VERSION 5.7 ;
  NOWIREEXTENSIONATPIN ON ;
  DIVIDERCHAR "/" ;
  BUSBITCHARS "[]" ;
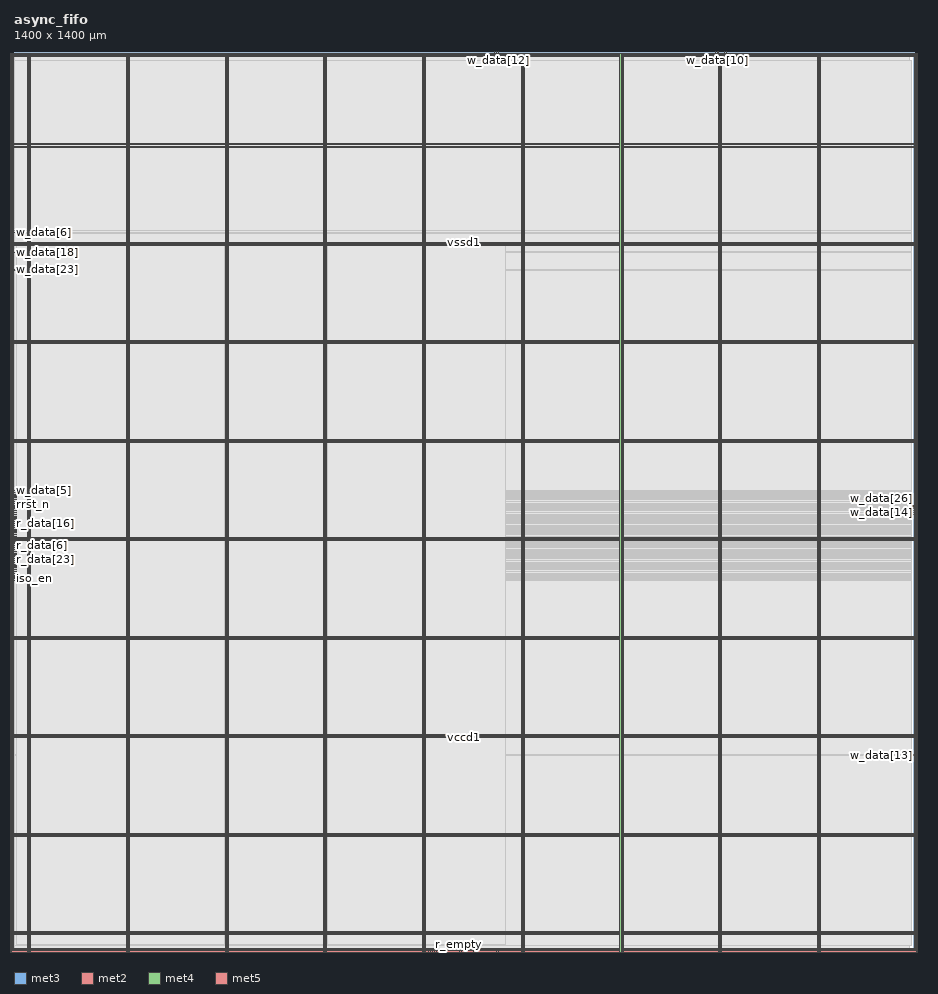
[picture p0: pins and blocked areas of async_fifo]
MACRO async_fifo
  CLASS BLOCK ;
  FOREIGN async_fifo ;
  ORIGIN 0.000 0.000 ;
  SIZE 1400.000 BY 1400.000 ;
  PIN iso_en
    DIRECTION INPUT ;
    USE SIGNAL ;
    ANTENNAGATEAREA 0.159000 ;
    PORT
      LAYER met3 ;
        RECT 0.000 581.440 4.000 582.040 ;
    END
  END iso_en
  PIN r_data[0]
    DIRECTION OUTPUT ;
    USE SIGNAL ;
    ANTENNADIFFAREA 3.180800 ;
    PORT
      LAYER met3 ;
        RECT 0.000 697.040 4.000 697.640 ;
    END
  END r_data[0]
  PIN r_data[10]
    DIRECTION OUTPUT ;
    USE SIGNAL ;
    ANTENNADIFFAREA 3.180800 ;
    PORT
      LAYER met3 ;
        RECT 0.000 693.640 4.000 694.240 ;
    END
  END r_data[10]
  PIN r_data[11]
    DIRECTION OUTPUT ;
    USE SIGNAL ;
    ANTENNADIFFAREA 3.180800 ;
    PORT
      LAYER met3 ;
        RECT 0.000 676.640 4.000 677.240 ;
    END
  END r_data[11]
  PIN r_data[12]
    DIRECTION OUTPUT ;
    USE SIGNAL ;
    ANTENNADIFFAREA 3.180800 ;
    PORT
      LAYER met3 ;
        RECT 0.000 584.840 4.000 585.440 ;
    END
  END r_data[12]
  PIN r_data[13]
    DIRECTION OUTPUT ;
    USE SIGNAL ;
    ANTENNADIFFAREA 3.180800 ;
    PORT
      LAYER met3 ;
        RECT 0.000 595.040 4.000 595.640 ;
    END
  END r_data[13]
  PIN r_data[14]
    DIRECTION OUTPUT ;
    USE SIGNAL ;
    ANTENNADIFFAREA 3.180800 ;
    PORT
      LAYER met3 ;
        RECT 0.000 629.040 4.000 629.640 ;
    END
  END r_data[14]
  PIN r_data[15]
    DIRECTION OUTPUT ;
    USE SIGNAL ;
    ANTENNADIFFAREA 3.180800 ;
    PORT
      LAYER met3 ;
        RECT 0.000 673.240 4.000 673.840 ;
    END
  END r_data[15]
  PIN r_data[16]
    DIRECTION OUTPUT ;
    USE SIGNAL ;
    ANTENNADIFFAREA 3.180800 ;
    PORT
      LAYER met3 ;
        RECT 0.000 666.440 4.000 667.040 ;
    END
  END r_data[16]
  PIN r_data[17]
    DIRECTION OUTPUT ;
    USE SIGNAL ;
    ANTENNADIFFAREA 3.180800 ;
    PORT
      LAYER met3 ;
        RECT 0.000 635.840 4.000 636.440 ;
    END
  END r_data[17]
  PIN r_data[18]
    DIRECTION OUTPUT ;
    USE SIGNAL ;
    ANTENNADIFFAREA 3.180800 ;
    PORT
      LAYER met3 ;
        RECT 0.000 680.040 4.000 680.640 ;
    END
  END r_data[18]
  PIN r_data[19]
    DIRECTION OUTPUT ;
    USE SIGNAL ;
    ANTENNADIFFAREA 3.180800 ;
    PORT
      LAYER met3 ;
        RECT 0.000 669.840 4.000 670.440 ;
    END
  END r_data[19]
  PIN r_data[1]
    DIRECTION OUTPUT ;
    USE SIGNAL ;
    ANTENNADIFFAREA 3.180800 ;
    PORT
      LAYER met3 ;
        RECT 0.000 618.840 4.000 619.440 ;
    END
  END r_data[1]
  PIN r_data[20]
    DIRECTION OUTPUT ;
    USE SIGNAL ;
    ANTENNADIFFAREA 3.180800 ;
    PORT
      LAYER met3 ;
        RECT 0.000 642.640 4.000 643.240 ;
    END
  END r_data[20]
  PIN r_data[21]
    DIRECTION OUTPUT ;
    USE SIGNAL ;
    ANTENNADIFFAREA 3.180800 ;
    PORT
      LAYER met3 ;
        RECT 0.000 612.040 4.000 612.640 ;
    END
  END r_data[21]
  PIN r_data[22]
    DIRECTION OUTPUT ;
    USE SIGNAL ;
    ANTENNADIFFAREA 3.180800 ;
    PORT
      LAYER met3 ;
        RECT 0.000 622.240 4.000 622.840 ;
    END
  END r_data[22]
  PIN r_data[23]
    DIRECTION OUTPUT ;
    USE SIGNAL ;
    ANTENNADIFFAREA 3.180800 ;
    PORT
      LAYER met3 ;
        RECT 0.000 598.440 4.000 599.040 ;
    END
  END r_data[23]
  PIN r_data[24]
    DIRECTION OUTPUT ;
    USE SIGNAL ;
    ANTENNADIFFAREA 3.180800 ;
    PORT
      LAYER met3 ;
        RECT 0.000 659.640 4.000 660.240 ;
    END
  END r_data[24]
  PIN r_data[25]
    DIRECTION OUTPUT ;
    USE SIGNAL ;
    ANTENNADIFFAREA 3.180800 ;
    PORT
      LAYER met3 ;
        RECT 0.000 608.640 4.000 609.240 ;
    END
  END r_data[25]
  PIN r_data[26]
    DIRECTION OUTPUT ;
    USE SIGNAL ;
    ANTENNADIFFAREA 3.180800 ;
    PORT
      LAYER met3 ;
        RECT 0.000 601.840 4.000 602.440 ;
    END
  END r_data[26]
  PIN r_data[27]
    DIRECTION OUTPUT ;
    USE SIGNAL ;
    ANTENNADIFFAREA 3.180800 ;
    PORT
      LAYER met3 ;
        RECT 0.000 663.040 4.000 663.640 ;
    END
  END r_data[27]
  PIN r_data[28]
    DIRECTION OUTPUT ;
    USE SIGNAL ;
    ANTENNADIFFAREA 3.180800 ;
    PORT
      LAYER met3 ;
        RECT 0.000 591.640 4.000 592.240 ;
    END
  END r_data[28]
  PIN r_data[29]
    DIRECTION OUTPUT ;
    USE SIGNAL ;
    ANTENNADIFFAREA 3.180800 ;
    PORT
      LAYER met3 ;
        RECT 0.000 690.240 4.000 690.840 ;
    END
  END r_data[29]
  PIN r_data[2]
    DIRECTION OUTPUT ;
    USE SIGNAL ;
    ANTENNADIFFAREA 3.180800 ;
    PORT
      LAYER met3 ;
        RECT 0.000 588.240 4.000 588.840 ;
    END
  END r_data[2]
  PIN r_data[30]
    DIRECTION OUTPUT ;
    USE SIGNAL ;
    ANTENNADIFFAREA 3.180800 ;
    PORT
      LAYER met3 ;
        RECT 0.000 605.240 4.000 605.840 ;
    END
  END r_data[30]
  PIN r_data[31]
    DIRECTION OUTPUT ;
    USE SIGNAL ;
    ANTENNADIFFAREA 3.180800 ;
    PORT
      LAYER met3 ;
        RECT 0.000 615.440 4.000 616.040 ;
    END
  END r_data[31]
  PIN r_data[3]
    DIRECTION OUTPUT ;
    USE SIGNAL ;
    ANTENNADIFFAREA 3.180800 ;
    PORT
      LAYER met3 ;
        RECT 0.000 646.040 4.000 646.640 ;
    END
  END r_data[3]
  PIN r_data[4]
    DIRECTION OUTPUT ;
    USE SIGNAL ;
    ANTENNADIFFAREA 3.180800 ;
    PORT
      LAYER met3 ;
        RECT 0.000 625.640 4.000 626.240 ;
    END
  END r_data[4]
  PIN r_data[5]
    DIRECTION OUTPUT ;
    USE SIGNAL ;
    ANTENNADIFFAREA 3.180800 ;
    PORT
      LAYER met3 ;
        RECT 0.000 656.240 4.000 656.840 ;
    END
  END r_data[5]
  PIN r_data[6]
    DIRECTION OUTPUT ;
    USE SIGNAL ;
    ANTENNADIFFAREA 3.180800 ;
    PORT
      LAYER met3 ;
        RECT 0.000 632.440 4.000 633.040 ;
    END
  END r_data[6]
  PIN r_data[7]
    DIRECTION OUTPUT ;
    USE SIGNAL ;
    ANTENNADIFFAREA 3.180800 ;
    PORT
      LAYER met3 ;
        RECT 0.000 649.440 4.000 650.040 ;
    END
  END r_data[7]
  PIN r_data[8]
    DIRECTION OUTPUT ;
    USE SIGNAL ;
    ANTENNADIFFAREA 3.180800 ;
    PORT
      LAYER met3 ;
        RECT 0.000 652.840 4.000 653.440 ;
    END
  END r_data[8]
  PIN r_data[9]
    DIRECTION OUTPUT ;
    USE SIGNAL ;
    ANTENNADIFFAREA 3.180800 ;
    PORT
      LAYER met3 ;
        RECT 0.000 639.240 4.000 639.840 ;
    END
  END r_data[9]
  PIN r_empty
    DIRECTION OUTPUT ;
    USE SIGNAL ;
    ANTENNADIFFAREA 3.180800 ;
    PORT
      LAYER met2 ;
        RECT 692.390 0.000 692.670 4.000 ;
    END
  END r_empty
  PIN r_inc
    DIRECTION INPUT ;
    USE SIGNAL ;
    ANTENNAGATEAREA 0.426000 ;
    PORT
      LAYER met2 ;
        RECT 695.610 0.000 695.890 4.000 ;
    END
  END r_inc
  PIN rclk
    DIRECTION INPUT ;
    USE SIGNAL ;
    ANTENNAGATEAREA 0.852000 ;
    PORT
      LAYER met3 ;
        RECT 0.000 686.840 4.000 687.440 ;
    END
  END rclk
  PIN rrst_n
    DIRECTION INPUT ;
    USE SIGNAL ;
    ANTENNAGATEAREA 0.990000 ;
    PORT
      LAYER met3 ;
        RECT 0.000 683.440 4.000 684.040 ;
    END
  END rrst_n
  PIN vccd1
    DIRECTION INOUT ;
    USE POWER ;
    PORT
      LAYER met4 ;
        RECT -2.080 3.280 -0.480 1394.800 ;
    END
    PORT
      LAYER met5 ;
        RECT -2.080 3.280 1401.860 4.880 ;
    END
    PORT
      LAYER met5 ;
        RECT -2.080 1393.200 1401.860 1394.800 ;
    END
    PORT
      LAYER met4 ;
        RECT 1400.260 3.280 1401.860 1394.800 ;
    END
    PORT
      LAYER met4 ;
        RECT 21.040 -0.020 22.640 1398.100 ;
    END
    PORT
      LAYER met4 ;
        RECT 174.640 -0.020 176.240 1398.100 ;
    END
    PORT
      LAYER met4 ;
        RECT 328.240 -0.020 329.840 1398.100 ;
    END
    PORT
      LAYER met4 ;
        RECT 481.840 -0.020 483.440 1398.100 ;
    END
    PORT
      LAYER met4 ;
        RECT 635.440 -0.020 637.040 1398.100 ;
    END
    PORT
      LAYER met4 ;
        RECT 789.040 -0.020 790.640 1398.100 ;
    END
    PORT
      LAYER met4 ;
        RECT 942.640 -0.020 944.240 1398.100 ;
    END
    PORT
      LAYER met4 ;
        RECT 1096.240 -0.020 1097.840 1398.100 ;
    END
    PORT
      LAYER met4 ;
        RECT 1249.840 -0.020 1251.440 1398.100 ;
    END
    PORT
      LAYER met5 ;
        RECT -5.380 26.730 1405.160 28.330 ;
    END
    PORT
      LAYER met5 ;
        RECT -5.380 179.910 1405.160 181.510 ;
    END
    PORT
      LAYER met5 ;
        RECT -5.380 333.090 1405.160 334.690 ;
    END
    PORT
      LAYER met5 ;
        RECT -5.380 486.270 1405.160 487.870 ;
    END
    PORT
      LAYER met5 ;
        RECT -5.380 639.450 1405.160 641.050 ;
    END
    PORT
      LAYER met5 ;
        RECT -5.380 792.630 1405.160 794.230 ;
    END
    PORT
      LAYER met5 ;
        RECT -5.380 945.810 1405.160 947.410 ;
    END
    PORT
      LAYER met5 ;
        RECT -5.380 1098.990 1405.160 1100.590 ;
    END
    PORT
      LAYER met5 ;
        RECT -5.380 1252.170 1405.160 1253.770 ;
    END
  END vccd1
  PIN vssd1
    DIRECTION INOUT ;
    USE GROUND ;
    PORT
      LAYER met4 ;
        RECT -5.380 -0.020 -3.780 1398.100 ;
    END
    PORT
      LAYER met5 ;
        RECT -5.380 -0.020 1405.160 1.580 ;
    END
    PORT
      LAYER met5 ;
        RECT -5.380 1396.500 1405.160 1398.100 ;
    END
    PORT
      LAYER met4 ;
        RECT 1403.560 -0.020 1405.160 1398.100 ;
    END
    PORT
      LAYER met4 ;
        RECT 24.340 -0.020 25.940 1398.100 ;
    END
    PORT
      LAYER met4 ;
        RECT 177.940 -0.020 179.540 1398.100 ;
    END
    PORT
      LAYER met4 ;
        RECT 331.540 -0.020 333.140 1398.100 ;
    END
    PORT
      LAYER met4 ;
        RECT 485.140 -0.020 486.740 1398.100 ;
    END
    PORT
      LAYER met4 ;
        RECT 638.740 -0.020 640.340 1398.100 ;
    END
    PORT
      LAYER met4 ;
        RECT 792.340 -0.020 793.940 1398.100 ;
    END
    PORT
      LAYER met4 ;
        RECT 945.940 -0.020 947.540 1398.100 ;
    END
    PORT
      LAYER met4 ;
        RECT 1099.540 -0.020 1101.140 1398.100 ;
    END
    PORT
      LAYER met4 ;
        RECT 1253.140 -0.020 1254.740 1398.100 ;
    END
    PORT
      LAYER met5 ;
        RECT -5.380 30.030 1405.160 31.630 ;
    END
    PORT
      LAYER met5 ;
        RECT -5.380 183.210 1405.160 184.810 ;
    END
    PORT
      LAYER met5 ;
        RECT -5.380 336.390 1405.160 337.990 ;
    END
    PORT
      LAYER met5 ;
        RECT -5.380 489.570 1405.160 491.170 ;
    END
    PORT
      LAYER met5 ;
        RECT -5.380 642.750 1405.160 644.350 ;
    END
    PORT
      LAYER met5 ;
        RECT -5.380 795.930 1405.160 797.530 ;
    END
    PORT
      LAYER met5 ;
        RECT -5.380 949.110 1405.160 950.710 ;
    END
    PORT
      LAYER met5 ;
        RECT -5.380 1102.290 1405.160 1103.890 ;
    END
    PORT
      LAYER met5 ;
        RECT -5.380 1255.470 1405.160 1257.070 ;
    END
  END vssd1
  PIN w_data[0]
    DIRECTION INPUT ;
    USE SIGNAL ;
    ANTENNAGATEAREA 0.495000 ;
    PORT
      LAYER met3 ;
        RECT 1396.000 680.040 1400.000 680.640 ;
    END
  END w_data[0]
  PIN w_data[10]
    DIRECTION INPUT ;
    USE SIGNAL ;
    ANTENNAGATEAREA 0.852000 ;
    PORT
      LAYER met2 ;
        RECT 1094.890 1396.000 1095.170 1400.000 ;
    END
  END w_data[10]
  PIN w_data[11]
    DIRECTION INPUT ;
    USE SIGNAL ;
    ANTENNAGATEAREA 0.852000 ;
    PORT
      LAYER met2 ;
        RECT 644.090 0.000 644.370 4.000 ;
    END
  END w_data[11]
  PIN w_data[12]
    DIRECTION INPUT ;
    USE SIGNAL ;
    ANTENNAGATEAREA 0.852000 ;
    PORT
      LAYER met2 ;
        RECT 753.570 1396.000 753.850 1400.000 ;
    END
  END w_data[12]
  PIN w_data[13]
    DIRECTION INPUT ;
    USE SIGNAL ;
    ANTENNAGATEAREA 0.495000 ;
    PORT
      LAYER met3 ;
        RECT 1396.000 306.040 1400.000 306.640 ;
    END
  END w_data[13]
  PIN w_data[14]
    DIRECTION INPUT ;
    USE SIGNAL ;
    ANTENNAGATEAREA 0.852000 ;
    PORT
      LAYER met3 ;
        RECT 1396.000 683.440 1400.000 684.040 ;
    END
  END w_data[14]
  PIN w_data[15]
    DIRECTION INPUT ;
    USE SIGNAL ;
    ANTENNAGATEAREA 0.247500 ;
    PORT
      LAYER met2 ;
        RECT 750.350 1396.000 750.630 1400.000 ;
    END
  END w_data[15]
  PIN w_data[16]
    DIRECTION INPUT ;
    USE SIGNAL ;
    ANTENNAGATEAREA 0.852000 ;
    PORT
      LAYER met3 ;
        RECT 0.000 714.040 4.000 714.640 ;
    END
  END w_data[16]
  PIN w_data[17]
    DIRECTION INPUT ;
    USE SIGNAL ;
    ANTENNAGATEAREA 0.990000 ;
    PORT
      LAYER met2 ;
        RECT 1107.770 1396.000 1108.050 1400.000 ;
    END
  END w_data[17]
  PIN w_data[18]
    DIRECTION INPUT ;
    USE SIGNAL ;
    ANTENNAGATEAREA 0.852000 ;
    PORT
      LAYER met3 ;
        RECT 0.000 1088.040 4.000 1088.640 ;
    END
  END w_data[18]
  PIN w_data[19]
    DIRECTION INPUT ;
    USE SIGNAL ;
    ANTENNAGATEAREA 0.852000 ;
    PORT
      LAYER met2 ;
        RECT 647.310 0.000 647.590 4.000 ;
    END
  END w_data[19]
  PIN w_data[1]
    DIRECTION INPUT ;
    USE SIGNAL ;
    ANTENNAGATEAREA 0.852000 ;
    PORT
      LAYER met3 ;
        RECT 1396.000 686.840 1400.000 687.440 ;
    END
  END w_data[1]
  PIN w_data[20]
    DIRECTION INPUT ;
    USE SIGNAL ;
    ANTENNAGATEAREA 0.852000 ;
    PORT
      LAYER met2 ;
        RECT 650.530 0.000 650.810 4.000 ;
    END
  END w_data[20]
  PIN w_data[21]
    DIRECTION INPUT ;
    USE SIGNAL ;
    ANTENNAGATEAREA 0.990000 ;
    PORT
      LAYER met2 ;
        RECT 1091.670 1396.000 1091.950 1400.000 ;
    END
  END w_data[21]
  PIN w_data[22]
    DIRECTION INPUT ;
    USE SIGNAL ;
    ANTENNAGATEAREA 0.426000 ;
    PORT
      LAYER met3 ;
        RECT 1396.000 690.240 1400.000 690.840 ;
    END
  END w_data[22]
  PIN w_data[23]
    DIRECTION INPUT ;
    USE SIGNAL ;
    ANTENNAGATEAREA 0.852000 ;
    PORT
      LAYER met3 ;
        RECT 0.000 1060.840 4.000 1061.440 ;
    END
  END w_data[23]
  PIN w_data[24]
    DIRECTION INPUT ;
    USE SIGNAL ;
    ANTENNAGATEAREA 0.852000 ;
    PORT
      LAYER met2 ;
        RECT 653.750 0.000 654.030 4.000 ;
    END
  END w_data[24]
  PIN w_data[25]
    DIRECTION INPUT ;
    USE SIGNAL ;
    ANTENNAGATEAREA 0.990000 ;
    PORT
      LAYER met2 ;
        RECT 747.130 1396.000 747.410 1400.000 ;
    END
  END w_data[25]
  PIN w_data[26]
    DIRECTION INPUT ;
    USE SIGNAL ;
    ANTENNAGATEAREA 0.495000 ;
    PORT
      LAYER met3 ;
        RECT 1396.000 693.640 1400.000 694.240 ;
    END
  END w_data[26]
  PIN w_data[27]
    DIRECTION INPUT ;
    USE SIGNAL ;
    ANTENNAGATEAREA 0.852000 ;
    PORT
      LAYER met2 ;
        RECT 656.970 0.000 657.250 4.000 ;
    END
  END w_data[27]
  PIN w_data[28]
    DIRECTION INPUT ;
    USE SIGNAL ;
    ANTENNAGATEAREA 0.990000 ;
    PORT
      LAYER met3 ;
        RECT 0.000 710.640 4.000 711.240 ;
    END
  END w_data[28]
  PIN w_data[29]
    DIRECTION INPUT ;
    USE SIGNAL ;
    ANTENNAGATEAREA 0.852000 ;
    PORT
      LAYER met2 ;
        RECT 660.190 0.000 660.470 4.000 ;
    END
  END w_data[29]
  PIN w_data[2]
    DIRECTION INPUT ;
    USE SIGNAL ;
    ANTENNAGATEAREA 0.852000 ;
    PORT
      LAYER met3 ;
        RECT 0.000 707.240 4.000 707.840 ;
    END
  END w_data[2]
  PIN w_data[30]
    DIRECTION INPUT ;
    USE SIGNAL ;
    ANTENNAGATEAREA 0.990000 ;
    PORT
      LAYER met3 ;
        RECT 0.000 703.840 4.000 704.440 ;
    END
  END w_data[30]
  PIN w_data[31]
    DIRECTION INPUT ;
    USE SIGNAL ;
    ANTENNAGATEAREA 0.852000 ;
    PORT
      LAYER met2 ;
        RECT 663.410 0.000 663.690 4.000 ;
    END
  END w_data[31]
  PIN w_data[3]
    DIRECTION INPUT ;
    USE SIGNAL ;
    ANTENNAGATEAREA 0.852000 ;
    PORT
      LAYER met3 ;
        RECT 0.000 700.440 4.000 701.040 ;
    END
  END w_data[3]
  PIN w_data[4]
    DIRECTION INPUT ;
    USE SIGNAL ;
    ANTENNAGATEAREA 0.990000 ;
    PORT
      LAYER met3 ;
        RECT 0.000 578.040 4.000 578.640 ;
    END
  END w_data[4]
  PIN w_data[5]
    DIRECTION INPUT ;
    USE SIGNAL ;
    ANTENNAGATEAREA 0.990000 ;
    PORT
      LAYER met3 ;
        RECT 0.000 717.440 4.000 718.040 ;
    END
  END w_data[5]
  PIN w_data[6]
    DIRECTION INPUT ;
    USE SIGNAL ;
    ANTENNAGATEAREA 0.852000 ;
    PORT
      LAYER met3 ;
        RECT 0.000 1118.640 4.000 1119.240 ;
    END
  END w_data[6]
  PIN w_data[7]
    DIRECTION INPUT ;
    USE SIGNAL ;
    ANTENNAGATEAREA 0.852000 ;
    PORT
      LAYER met2 ;
        RECT 666.630 0.000 666.910 4.000 ;
    END
  END w_data[7]
  PIN w_data[8]
    DIRECTION INPUT ;
    USE SIGNAL ;
    ANTENNAGATEAREA 0.213000 ;
    PORT
      LAYER met2 ;
        RECT 1104.550 1396.000 1104.830 1400.000 ;
    END
  END w_data[8]
  PIN w_data[9]
    DIRECTION INPUT ;
    USE SIGNAL ;
    ANTENNAGATEAREA 0.990000 ;
    PORT
      LAYER met2 ;
        RECT 669.850 0.000 670.130 4.000 ;
    END
  END w_data[9]
  PIN w_full
    DIRECTION OUTPUT ;
    USE SIGNAL ;
    ANTENNADIFFAREA 3.180800 ;
    PORT
      LAYER met2 ;
        RECT 750.350 0.000 750.630 4.000 ;
    END
  END w_full
  PIN w_inc
    DIRECTION INPUT ;
    USE SIGNAL ;
    ANTENNAGATEAREA 0.426000 ;
    PORT
      LAYER met2 ;
        RECT 753.570 0.000 753.850 4.000 ;
    END
  END w_inc
  PIN wclk
    DIRECTION INPUT ;
    USE SIGNAL ;
    ANTENNAGATEAREA 1.286700 ;
    ANTENNADIFFAREA 0.434700 ;
    PORT
      LAYER met3 ;
        RECT 0.000 1122.040 4.000 1122.640 ;
    END
  END wclk
  PIN wrst_n
    DIRECTION INPUT ;
    USE SIGNAL ;
    ANTENNAGATEAREA 0.126000 ;
    PORT
      LAYER met2 ;
        RECT 714.930 0.000 715.210 4.000 ;
    END
  END wrst_n
  OBS
      LAYER nwell ;
        RECT 5.330 10.795 1394.450 1387.285 ;
      LAYER li1 ;
        RECT 5.520 10.795 1394.260 1387.285 ;
      LAYER met1 ;
        RECT 4.210 10.640 1394.260 1387.440 ;
      LAYER met2 ;
        RECT 0.550 1395.720 746.850 1396.000 ;
        RECT 747.690 1395.720 750.070 1396.000 ;
        RECT 750.910 1395.720 753.290 1396.000 ;
        RECT 754.130 1395.720 1091.390 1396.000 ;
        RECT 1092.230 1395.720 1094.610 1396.000 ;
        RECT 1095.450 1395.720 1104.270 1396.000 ;
        RECT 1105.110 1395.720 1107.490 1396.000 ;
        RECT 1108.330 1395.720 1392.790 1396.000 ;
        RECT 0.550 4.280 1392.790 1395.720 ;
        RECT 0.550 4.000 643.810 4.280 ;
        RECT 644.650 4.000 647.030 4.280 ;
        RECT 647.870 4.000 650.250 4.280 ;
        RECT 651.090 4.000 653.470 4.280 ;
        RECT 654.310 4.000 656.690 4.280 ;
        RECT 657.530 4.000 659.910 4.280 ;
        RECT 660.750 4.000 663.130 4.280 ;
        RECT 663.970 4.000 666.350 4.280 ;
        RECT 667.190 4.000 669.570 4.280 ;
        RECT 670.410 4.000 692.110 4.280 ;
        RECT 692.950 4.000 695.330 4.280 ;
        RECT 696.170 4.000 714.650 4.280 ;
        RECT 715.490 4.000 750.070 4.280 ;
        RECT 750.910 4.000 753.290 4.280 ;
        RECT 754.130 4.000 1392.790 4.280 ;
      LAYER met3 ;
        RECT 0.525 1123.040 1396.000 1387.365 ;
        RECT 4.400 1121.640 1396.000 1123.040 ;
        RECT 0.525 1119.640 1396.000 1121.640 ;
        RECT 4.400 1118.240 1396.000 1119.640 ;
        RECT 0.525 1089.040 1396.000 1118.240 ;
        RECT 4.400 1087.640 1396.000 1089.040 ;
        RECT 0.525 1061.840 1396.000 1087.640 ;
        RECT 4.400 1060.440 1396.000 1061.840 ;
        RECT 0.525 718.440 1396.000 1060.440 ;
        RECT 4.400 717.040 1396.000 718.440 ;
        RECT 0.525 715.040 1396.000 717.040 ;
        RECT 4.400 713.640 1396.000 715.040 ;
        RECT 0.525 711.640 1396.000 713.640 ;
        RECT 4.400 710.240 1396.000 711.640 ;
        RECT 0.525 708.240 1396.000 710.240 ;
        RECT 4.400 706.840 1396.000 708.240 ;
        RECT 0.525 704.840 1396.000 706.840 ;
        RECT 4.400 703.440 1396.000 704.840 ;
        RECT 0.525 701.440 1396.000 703.440 ;
        RECT 4.400 700.040 1396.000 701.440 ;
        RECT 0.525 698.040 1396.000 700.040 ;
        RECT 4.400 696.640 1396.000 698.040 ;
        RECT 0.525 694.640 1396.000 696.640 ;
        RECT 4.400 693.240 1395.600 694.640 ;
        RECT 0.525 691.240 1396.000 693.240 ;
        RECT 4.400 689.840 1395.600 691.240 ;
        RECT 0.525 687.840 1396.000 689.840 ;
        RECT 4.400 686.440 1395.600 687.840 ;
        RECT 0.525 684.440 1396.000 686.440 ;
        RECT 4.400 683.040 1395.600 684.440 ;
        RECT 0.525 681.040 1396.000 683.040 ;
        RECT 4.400 679.640 1395.600 681.040 ;
        RECT 0.525 677.640 1396.000 679.640 ;
        RECT 4.400 676.240 1396.000 677.640 ;
        RECT 0.525 674.240 1396.000 676.240 ;
        RECT 4.400 672.840 1396.000 674.240 ;
        RECT 0.525 670.840 1396.000 672.840 ;
        RECT 4.400 669.440 1396.000 670.840 ;
        RECT 0.525 667.440 1396.000 669.440 ;
        RECT 4.400 666.040 1396.000 667.440 ;
        RECT 0.525 664.040 1396.000 666.040 ;
        RECT 4.400 662.640 1396.000 664.040 ;
        RECT 0.525 660.640 1396.000 662.640 ;
        RECT 4.400 659.240 1396.000 660.640 ;
        RECT 0.525 657.240 1396.000 659.240 ;
        RECT 4.400 655.840 1396.000 657.240 ;
        RECT 0.525 653.840 1396.000 655.840 ;
        RECT 4.400 652.440 1396.000 653.840 ;
        RECT 0.525 650.440 1396.000 652.440 ;
        RECT 4.400 649.040 1396.000 650.440 ;
        RECT 0.525 647.040 1396.000 649.040 ;
        RECT 4.400 645.640 1396.000 647.040 ;
        RECT 0.525 643.640 1396.000 645.640 ;
        RECT 4.400 642.240 1396.000 643.640 ;
        RECT 0.525 640.240 1396.000 642.240 ;
        RECT 4.400 638.840 1396.000 640.240 ;
        RECT 0.525 636.840 1396.000 638.840 ;
        RECT 4.400 635.440 1396.000 636.840 ;
        RECT 0.525 633.440 1396.000 635.440 ;
        RECT 4.400 632.040 1396.000 633.440 ;
        RECT 0.525 630.040 1396.000 632.040 ;
        RECT 4.400 628.640 1396.000 630.040 ;
        RECT 0.525 626.640 1396.000 628.640 ;
        RECT 4.400 625.240 1396.000 626.640 ;
        RECT 0.525 623.240 1396.000 625.240 ;
        RECT 4.400 621.840 1396.000 623.240 ;
        RECT 0.525 619.840 1396.000 621.840 ;
        RECT 4.400 618.440 1396.000 619.840 ;
        RECT 0.525 616.440 1396.000 618.440 ;
        RECT 4.400 615.040 1396.000 616.440 ;
        RECT 0.525 613.040 1396.000 615.040 ;
        RECT 4.400 611.640 1396.000 613.040 ;
        RECT 0.525 609.640 1396.000 611.640 ;
        RECT 4.400 608.240 1396.000 609.640 ;
        RECT 0.525 606.240 1396.000 608.240 ;
        RECT 4.400 604.840 1396.000 606.240 ;
        RECT 0.525 602.840 1396.000 604.840 ;
        RECT 4.400 601.440 1396.000 602.840 ;
        RECT 0.525 599.440 1396.000 601.440 ;
        RECT 4.400 598.040 1396.000 599.440 ;
        RECT 0.525 596.040 1396.000 598.040 ;
        RECT 4.400 594.640 1396.000 596.040 ;
        RECT 0.525 592.640 1396.000 594.640 ;
        RECT 4.400 591.240 1396.000 592.640 ;
        RECT 0.525 589.240 1396.000 591.240 ;
        RECT 4.400 587.840 1396.000 589.240 ;
        RECT 0.525 585.840 1396.000 587.840 ;
        RECT 4.400 584.440 1396.000 585.840 ;
        RECT 0.525 582.440 1396.000 584.440 ;
        RECT 4.400 581.040 1396.000 582.440 ;
        RECT 0.525 579.040 1396.000 581.040 ;
        RECT 4.400 577.640 1396.000 579.040 ;
        RECT 0.525 307.040 1396.000 577.640 ;
        RECT 0.525 305.640 1395.600 307.040 ;
        RECT 0.525 10.715 1396.000 305.640 ;
      LAYER met4 ;
        RECT 3.975 11.735 20.640 1099.385 ;
        RECT 23.040 11.735 23.940 1099.385 ;
        RECT 26.340 11.735 174.240 1099.385 ;
        RECT 176.640 11.735 177.540 1099.385 ;
        RECT 179.940 11.735 327.840 1099.385 ;
        RECT 330.240 11.735 331.140 1099.385 ;
        RECT 333.540 11.735 481.440 1099.385 ;
        RECT 483.840 11.735 484.740 1099.385 ;
        RECT 487.140 11.735 635.040 1099.385 ;
        RECT 637.440 11.735 638.340 1099.385 ;
        RECT 640.740 11.735 765.145 1099.385 ;
  END
END async_fifo
END LIBRARY

